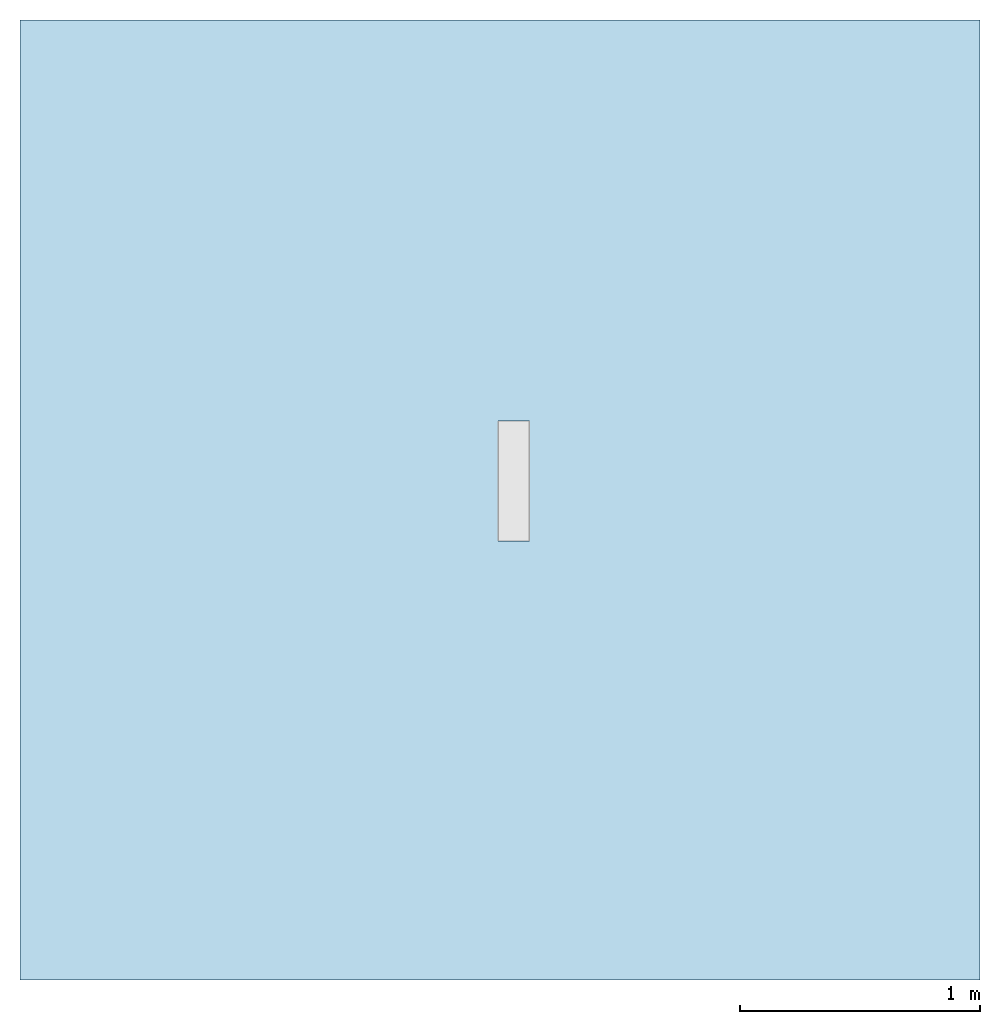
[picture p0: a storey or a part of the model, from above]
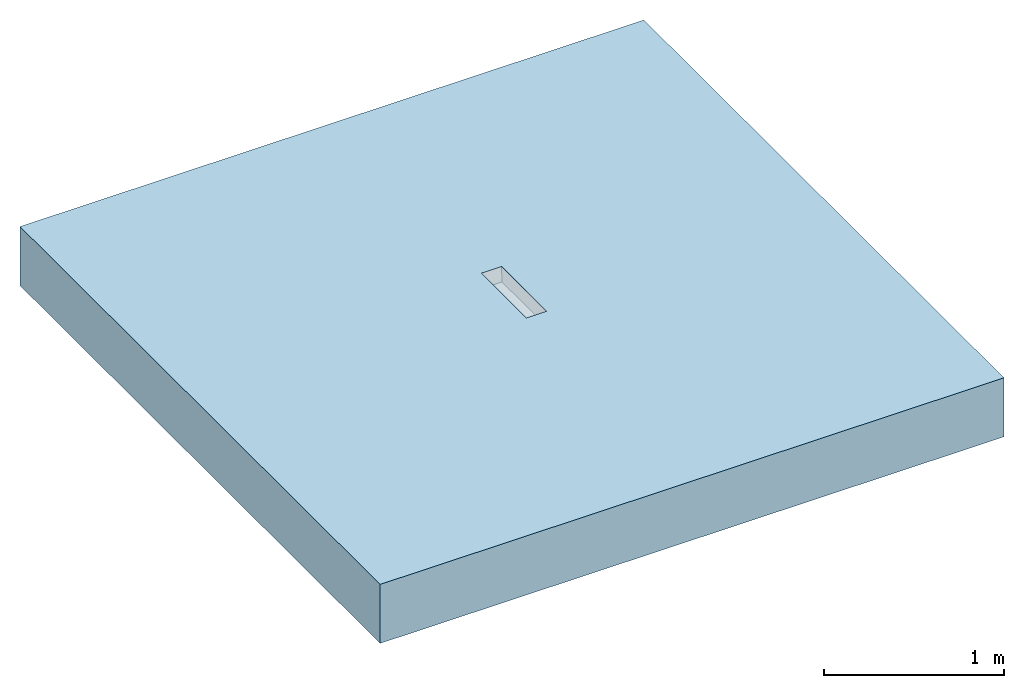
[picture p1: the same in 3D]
Properties of the parts of a building model (IFC2X3)

# File
Description: ViewDefinition [CoordinationView]
File name: Project Number
Time: 2014-06-06T14:24:06
Written by: The EXPRESS Data Manager Version 5.01.0100.02.64mod : 6 Jun 2012
Made in: 20130308_1515(x64) - Exporter 2014.0.2013.0308 - Default UI
Comment: STEP Physical File produced by: The EXPRESS Data Manager Version 5.01.0100.02.64mod : 6 Jun 2012 * Module: EDMstepFileFactory/EDMstandAlone * Creation date: Fri Jun 06 14:24:06 2014 * Host: IN-BLR-PC-0010 * Database: C:\Users\palleri\AppData\Local\Temp\{81463B04-0EC3-4DC1-A579-89FCD971B396}\ifc * Database version: 5507 * Database creation date: Fri Jun 06 14:24:05 2014 * Schema: IFC2X3 * Model: DataRepository.ifc * Model creation date: Fri Jun 06 14:24:06 2014 * Header model: DataRepository.ifc_HeaderModel * Header model creation date: Fri Jun 06 14:24:06 2014 * EDMuser: sdai-user * EDMgroup: sdai-group * License ID and type: 5605 : Permanent license. Expiry date: * EDMstepFileFactory options: 020000

# IfcProject, Project Number
LongName: Project Name; Phase: Project Status

# IfcSite, Default
RefLatitude: 42, 21, 30, 344238; RefLongitude: -71, -3, -35, -194702; RefElevation: 0 mm

# IfcBuilding
Pset_BuildingCommon - NumberOfStoreys: 1
Other - Project Number: Project Number; Client Name: Owner; Project Name: Project Name; Project Address: ## Street City, State Zip; Project Status: Project Status; Project Issue Date: Issue Date

# IfcBuildingStorey, Level 1
LongName: Level 1; Elevation: 0 mm
Constraints - Elevation Base: Project Base Point; Elevation: 0 mm
Graphics - Color: 0; Symbol: M_Level Head - Circle: M_Level Head - Circle; Line Weight: 1; Line Pattern: Center; Symbol at End 2 Default: yes; Symbol at End 1 Default: no
Dimensions - Computation Height: 0 mm
Identity Data - Structural: no; Name: Level 1; Building Story: yes

# IfcFlowTerminal: 36837 - Adjustable Channel - Intermediate Section - 500mm LG - Invert Depth 75/105mm, ACO Freedeck Adjustable Height Channel Intermediate Section Stainless Steel:36837 - Adjustable Channel - Intermediate Section - 500mm LG - Invert Depth 75/105mm:313968
In: Level 1
Material: Stainless Steel Grade 304
Construction - End Plate Invert 2: no; End Plate Invert 1: no; 36954 - Grating - Plain Mesh - Stainless Steel 304 - 500mm long: no; 00273 - Grating - Slotted Grating - Stainless Steel 304 - 500mm long: no; 36955 - Grating - Plain Mesh - Stainless Steel 304 - 1000mm long: yes; 00272 - Grating - Slotted Grating - Stainless Steel 304 - 1000mm long: no
Dimensions - Height @ Invert 1 (75 - 105mm): 105 mm; Height @ Invert 2 (75 - 105mm): 105 mm; Grating End Length: 500 mm; Channel End Length: -500 mm
Other - Height @ Invert 1 Min & Max: 105 mm; Height @ Invert 2 Min & Max: 105 mm; Top Piece Void Height @ Invert 1: 45 mm; Top Piece Void Height @ Invert 2: 45 mm; Nos: 16
Phasing - Phase Created: New Construction
Identity Data - Mark: 29; Watermarked With: BIM Manager Premium Suite; E-mail Technical: abdtechnical@aco.co.uk; E-mail Sales: abdcommercial@aco.co.uk; Website: www.acobd.com; Manufacturer: ACO Building Drainage; Telephone: +44 (0)1462 816666; Fax: +44 (0)1462 851490; Watermarked By: www.acobd.com; Watermark2: This file is water marked and users are prohibited to reproduce, adapt, distribute this information; Address: ACO Business Centre, Caxton Road, Bedford, MK41 0LF; Watermark1: This file is the property of ACO Technologies PLC
Constraints - Moves With Nearby Elements: no; Level: Level: Level 1
Pset_ManufacturerTypeInformation - Manufacturer: ACO Building Drainage
General - Installation Guidelines: X:\Electronic Literature\ABD Electronic Literature\Roof and Balcony Drainage\ACO Freedeck Brochure.pdf; Product Range: ACO Freedeck; Maintenance Guidelines: X:\Electronic Literature\ABD Electronic Literature\Roof and Balcony Drainage\ACO Freedeck Brochure.pdf; Price: POA - contact ACO; Channel Recyclable: Fully recyclable; NBS Specification: NBS Section R10 Gravity Rainwater Drainage Systems, Subsection 365; Channel Material: Stainless Steel Grade 304; Channel Colour: Mid Grey; Dimensions (LxWxH): 500 x 130 x 75/105; Product Type: Linear Deck Drainage System; Product Code: 36837; Weight (Kg): 3.3kg; Product Standard: BS EN 1433:2002, CE marked; Product Description: ACO Freedeck Adjustable Channel - Intermediate Section; Load Class: A15; Channel Recycled Material Content: 60 - 70 %
Model Properties - Grating Product Code 00272: Load Class A15 - Slotted Grating - 10 x 80mm Slot - Stainless Steel 304 - 1000mm long - 2.2kg; Grating Product Code 00273: Load Class A15 - Slotted Grating - 10 x 80mm Slot - Stainless Steel 304 - 500mm long - 1.0kg; Grating Product Code 36955: Load Class A15 - Mesh Grating - 14mm x 30mm Mesh - Stainless Steel 304 - 1000mm long - 3.0kg; Grating Product Code 36954: Load Class A15 - Mesh Grating - 14mm x 30mm Mesh - Stainless Steel 304 - 500mm long - 1.6kg; End Plate Product Code 36841: End Plate Stainless Steel 304 for Invert Depth - 75/105mm - 0.1Kg
Materials and Finishes - Material: Stainless Steel Grade 304

# IfcOpeningElement: Recess
In: Level 1
Dimensions - Perimeter: 16000 mm; Area: 16 m2; Thickness: 400 mm; Volume: 6.39306 m3
Constraints - Related to Mass: no; Level: Level: Level 1; Room Bounding: yes; Height Offset From Level: 0 mm
Structural - Enable Analytical Model: no; Structural: no
Phasing - Phase Created: New Construction
Analytical Properties - Thermal Resistance (R): 0.382409; Thermal mass: 604440; Roughness: 1; Heat Transfer Coefficient (U): 2.615; Absorptance: 0.1
Construction - Function: Interior; Default Thickness: 400 mm
Graphics - Coarse Scale Fill Color: 0
Materials and Finishes - Structural Material: Concrete, Broom Finish

# IfcSlab: Floor:Generic Floor - 400mm, Floor:Generic Floor - 400mm:193825
In: Level 1
PredefinedType: FLOOR; Material: Concrete, Broom Finish 400 mm
Dimensions - Perimeter: 16000 mm; Area: 16 m2; Thickness: 400 mm; Volume: 6.39306 m3
Constraints - Related to Mass: no; Level: Level: Level 1; Room Bounding: yes; Height Offset From Level: 0 mm
Structural - Enable Analytical Model: no; Structural: no
Phasing - Phase Created: New Construction
Pset_SlabCommon - Reference: Generic Floor - 400mm; IsExternal: no; LoadBearing: yes; ThermalTransmittance: 2.615 kg/K/s3
Analytical Properties - Thermal Resistance (R): 0.382409; Thermal mass: 604440; Roughness: 1; Heat Transfer Coefficient (U): 2.615; Absorptance: 0.1
Construction - Function: Interior; Default Thickness: 400 mm
Graphics - Coarse Scale Fill Color: 0
Materials and Finishes - Structural Material: Concrete, Broom Finish
